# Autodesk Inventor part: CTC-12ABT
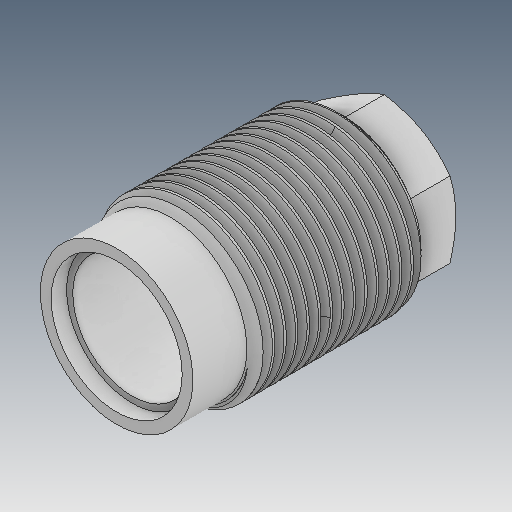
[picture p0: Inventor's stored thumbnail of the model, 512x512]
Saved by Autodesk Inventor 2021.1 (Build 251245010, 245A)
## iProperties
Created: 2018-08
Part Number: CTC-12ABT
Material: Ogólny
Document SubType Name: Modeling
Designer: user
Density: 1 g/cm^3
Appearance: Domyślna
Author: user
Revision Number: ÈÎºÎ
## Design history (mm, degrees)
feature "ÊäÈë1"
node "Bryła1"
